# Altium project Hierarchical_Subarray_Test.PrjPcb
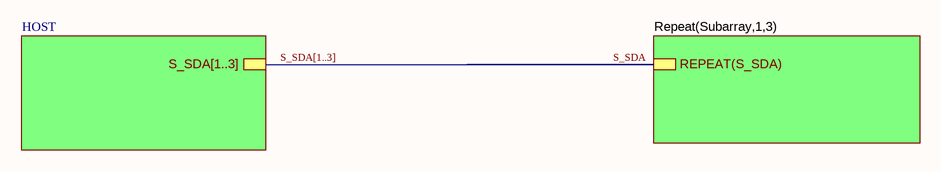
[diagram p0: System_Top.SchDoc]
4 sheets, 0 parts. Net scope: hierarchical (ports join the sheet entries above them; power ports are global).
Sheets:
  System_Top.SchDoc
    Subarray1 = Subarray.SchDoc
      AWR22431 = S_AWR2243.SchDoc
      AWR22432 = S_AWR2243.SchDoc
    Subarray2 = Subarray.SchDoc
      AWR22431 = S_AWR2243.SchDoc
      AWR22432 = S_AWR2243.SchDoc
    Subarray3 = Subarray.SchDoc
      AWR22431 = S_AWR2243.SchDoc
      AWR22432 = S_AWR2243.SchDoc
    HOST = HOST.SchDoc

## Sheet System_Top.SchDoc
size 431 x 279 mm; SheetNumber: 1; SheetTotal: 4; PageSetup: Record=PageOptions¦CenterHorizontal=True¦CenterVertical=True¦PrintScale=1.01¦XCorrection=1.00¦YCorrection=1.00¦PrintKind=1¦BorderSize=5000000¦LeftOffset=0¦BottomOffset=0¦Orientation=2¦PaperLength=1000¦PaperWidth=1000¦Scale=100¦PaperSource=7¦PrintQuality=600¦MediaType=1¦DitherType=10¦PaperKind=A3¦PrintScaleMode=1; ENG_APP_DATE: --/--/--; DSN_APP_DATE: --/--/--; CHK_APP_DATE: --/--/--

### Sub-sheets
HOST = HOST.SchDoc: S_SDA[1..3]
Repeat(Subarray,1,3) = Subarray.SchDoc: REPEAT(S_SDA)

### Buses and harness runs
bus S_SDA[1..3] = sheet HOST/S_SDA[1..3]

## Sheet Subarray.SchDoc
size 431 x 279 mm; SheetNumber: 2; SheetTotal: 4; PageSetup: Record=PageOptions¦CenterHorizontal=True¦CenterVertical=True¦PrintScale=1.01¦XCorrection=1.00¦YCorrection=1.00¦PrintKind=1¦BorderSize=5000000¦LeftOffset=0¦BottomOffset=0¦Orientation=2¦PaperLength=1000¦PaperWidth=1000¦Scale=100¦PaperSource=7¦PrintQuality=600¦MediaType=1¦DitherType=10¦PaperKind=A3¦PrintScaleMode=1; ENG_APP_DATE: --/--/--; DSN_APP_DATE: --/--/--; CHK_APP_DATE: --/--/--
Used 3 times, as channels Subarray1, Subarray2, Subarray3. Parts and nets are listed once, with the designators drawn on the sheet.

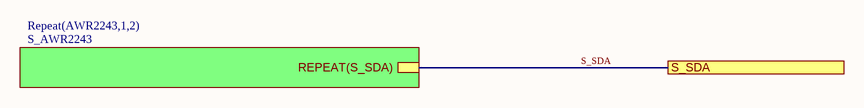
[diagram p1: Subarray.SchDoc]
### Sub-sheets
Repeat(AWR2243,1,2) = S_AWR2243: REPEAT(S_SDA)

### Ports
S_SDA

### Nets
S_SDA: port S_SDA, sheet Repeat(AWR2243,1,2)/REPEAT(S_SDA)

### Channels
Subarray1: ports S_SDA=S_SDA_Subarray1
Subarray2: ports S_SDA=S_SDA_Subarray2
Subarray3: ports S_SDA=S_SDA_Subarray3

## Sheet S_AWR2243.SchDoc
size 431 x 279 mm; SheetNumber: 3; SheetTotal: 4; PageSetup: Record=PageOptions¦CenterHorizontal=True¦CenterVertical=True¦PrintScale=1.01¦XCorrection=1.00¦YCorrection=1.00¦PrintKind=1¦BorderSize=5000000¦LeftOffset=0¦BottomOffset=0¦Orientation=2¦PaperLength=1000¦PaperWidth=1000¦Scale=100¦PaperSource=7¦PrintQuality=600¦MediaType=1¦DitherType=10¦PaperKind=A3¦PrintScaleMode=1; SPICEModelCacheFJOGIKSH: <root> / <DocumentId>FJOGIKSH</DocumentId> / </root>; ENG_APP_DATE: --/--/--; DSN_APP_DATE: --/--/--; CHK_APP_DATE: --/--/--
Used 6 times, as channels Subarray1/AWR22431, Subarray1/AWR22432, Subarray2/AWR22431, Subarray2/AWR22432, Subarray3/AWR22431, Subarray3/AWR22432. Parts and nets are listed once, with the designators drawn on the sheet.

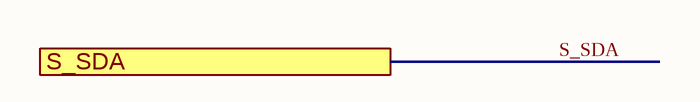
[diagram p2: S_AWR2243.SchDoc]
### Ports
S_SDA

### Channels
Subarray1/AWR22431: ports S_SDA=S_SDA_AWR22431
Subarray1/AWR22432: ports S_SDA=S_SDA_AWR22432
Subarray2/AWR22431: ports S_SDA=S_SDA_AWR22431
Subarray2/AWR22432: ports S_SDA=S_SDA_AWR22432
Subarray3/AWR22431: ports S_SDA=S_SDA_AWR22431
Subarray3/AWR22432: ports S_SDA=S_SDA_AWR22432

## Sheet HOST.SchDoc
size 431 x 279 mm; SheetNumber: 4; SheetTotal: 4; ENG_APP_DATE: --/--/--; DSN_APP_DATE: --/--/--; CHK_APP_DATE: --/--/--

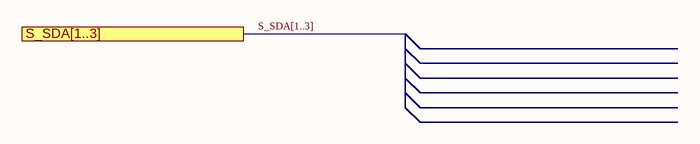
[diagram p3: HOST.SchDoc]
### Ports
S_SDA[1..3]

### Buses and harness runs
bus S_SDA[1..3] = port S_SDA[1..3]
